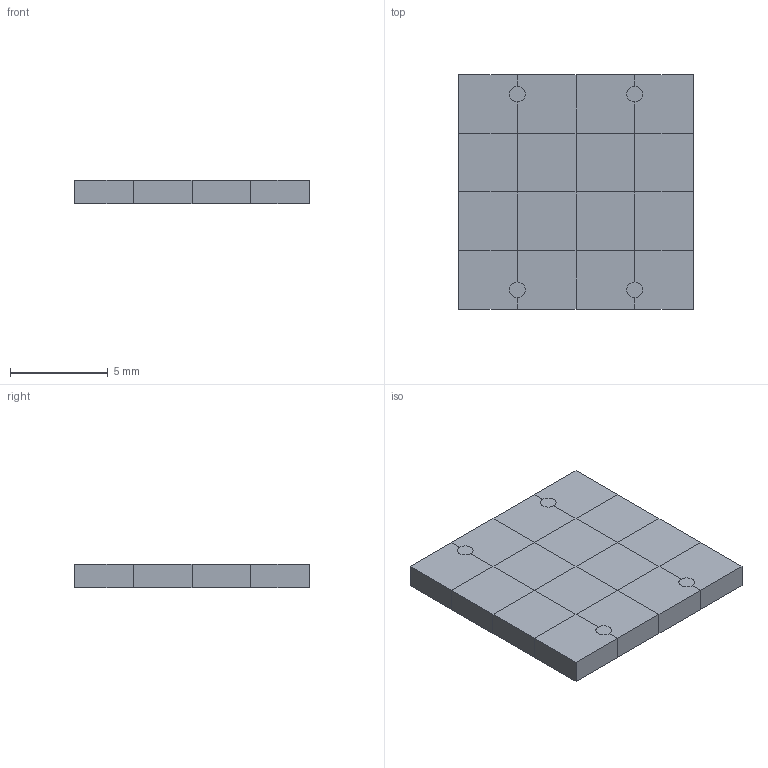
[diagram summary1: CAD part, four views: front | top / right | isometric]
STEP (ISO 10303-21) file: header records copied from the file, then geometry measured from it (millimetres).
FILE_DESCRIPTION(('Open CASCADE Model'),'2;1');
FILE_NAME('Open CASCADE Shape Model','2026-11-27T10:08:08',('Author'),( 'Open CASCADE'),'Open CASCADE STEP processor 7.9','Open CASCADE 7.9' ,'Unknown');
FILE_SCHEMA(('AUTOMOTIVE_DESIGN { 1 0 10303 214 1 1 1 1 }'));
Length unit declared in the file: millimetre
Products named in the file (3): manifold_N14; fluid; solid
Assembly tree (2 placements, depth 2):
  manifold_N14
    fluid
    solid
Bounding box: 12 x 12 x 1.2 mm (x, y, z)
Volume: 172.8 mm3; surface area: 1497 mm2
Topology: 2 solids, 2 shells, 1772 faces, 6308 edges, 3554 vertices
Faces by surface type: plane 1764, cylinder 8
Full cylindrical faces by diameter (mm): 0.8 x8
Entity records: 147670 total; most frequent: CARTESIAN_POINT 24301, DIRECTION 22490, LINE 18876, VECTOR 18876, ORIENTED_EDGE 12616, PCURVE 12616, DEFINITIONAL_REPRESENTATION 12616, EDGE_CURVE 6308
One B-rep face of a CAD part: STEP entity #79262.
In plain terms, the planar face has unit normal (0, 0, 1).
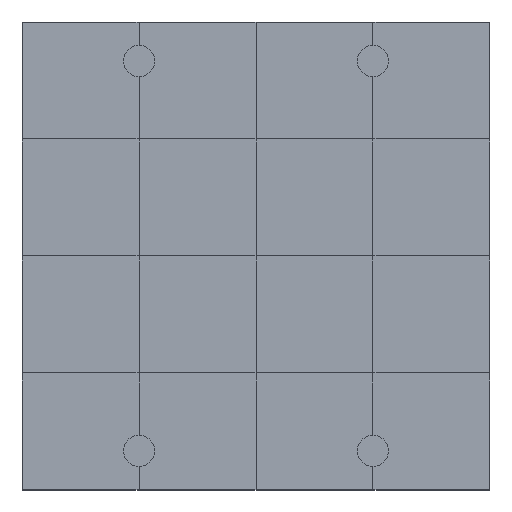
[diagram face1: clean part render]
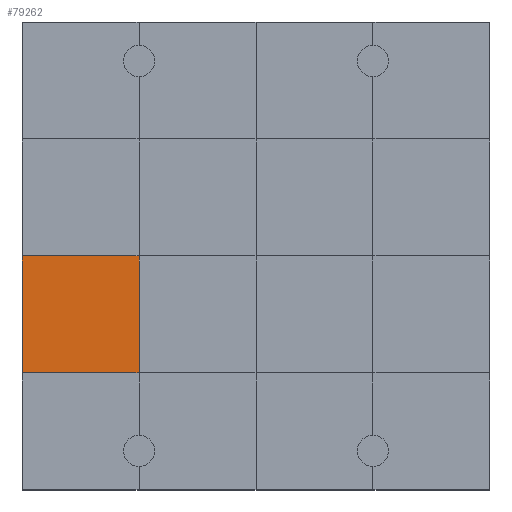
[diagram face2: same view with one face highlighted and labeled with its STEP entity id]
Its self-contained STEP definition (entity closure, numbers rounded to 3 decimals):
#78812 = VERTEX_POINT('',#78813);
#78813 = CARTESIAN_POINT('',(0.,3.,1.2));
#78827 = PLANE('',#78828);
#78828 = AXIS2_PLACEMENT_3D('',#78829,#78830,#78831);
#78829 = CARTESIAN_POINT('',(0.,3.,0.));
#78830 = DIRECTION('',(1.,0.,-0.));
#78831 = DIRECTION('',(0.,0.,1.));
#78853 = PLANE('',#78854);
#78854 = AXIS2_PLACEMENT_3D('',#78855,#78856,#78857);
#78855 = CARTESIAN_POINT('',(0.,0.,1.2));
#78856 = DIRECTION('',(0.,0.,1.));
#78857 = DIRECTION('',(1.,0.,-0.));
#79004 = VERTEX_POINT('',#79005);
#79005 = CARTESIAN_POINT('',(3.,3.,1.2));
#79026 = EDGE_CURVE('',#78812,#79004,#79027,.T.);
#79027 = SURFACE_CURVE('',#79028,(#79032,#79039),.PCURVE_S1.);
#79028 = LINE('',#79029,#79030);
#79029 = CARTESIAN_POINT('',(0.,3.,1.2));
#79030 = VECTOR('',#79031,1.);
#79031 = DIRECTION('',(1.,0.,-0.));
#79032 = PCURVE('',#78853,#79033);
#79033 = DEFINITIONAL_REPRESENTATION('',(#79034),#79038);
#79034 = LINE('',#79035,#79036);
#79035 = CARTESIAN_POINT('',(0.,3.));
#79036 = VECTOR('',#79037,1.);
#79037 = DIRECTION('',(1.,0.));
#79038 = ( GEOMETRIC_REPRESENTATION_CONTEXT(2) 
PARAMETRIC_REPRESENTATION_CONTEXT() REPRESENTATION_CONTEXT('2D SPACE',''
  ) );
#79039 = PCURVE('',#79040,#79045);
#79040 = PLANE('',#79041);
#79041 = AXIS2_PLACEMENT_3D('',#79042,#79043,#79044);
#79042 = CARTESIAN_POINT('',(0.,3.,1.2));
#79043 = DIRECTION('',(0.,0.,1.));
#79044 = DIRECTION('',(1.,0.,-0.));
#79045 = DEFINITIONAL_REPRESENTATION('',(#79046),#79050);
#79046 = LINE('',#79047,#79048);
#79047 = CARTESIAN_POINT('',(0.,0.));
#79048 = VECTOR('',#79049,1.);
#79049 = DIRECTION('',(1.,0.));
#79050 = ( GEOMETRIC_REPRESENTATION_CONTEXT(2) 
PARAMETRIC_REPRESENTATION_CONTEXT() REPRESENTATION_CONTEXT('2D SPACE',''
  ) );
#79085 = VERTEX_POINT('',#79086);
#79086 = CARTESIAN_POINT('',(0.,6.,1.2));
#79112 = EDGE_CURVE('',#78812,#79085,#79113,.T.);
#79113 = SURFACE_CURVE('',#79114,(#79118,#79125),.PCURVE_S1.);
#79114 = LINE('',#79115,#79116);
#79115 = CARTESIAN_POINT('',(0.,3.,1.2));
#79116 = VECTOR('',#79117,1.);
#79117 = DIRECTION('',(-0.,1.,0.));
#79118 = PCURVE('',#78827,#79119);
#79119 = DEFINITIONAL_REPRESENTATION('',(#79120),#79124);
#79120 = LINE('',#79121,#79122);
#79121 = CARTESIAN_POINT('',(1.2,0.));
#79122 = VECTOR('',#79123,1.);
#79123 = DIRECTION('',(0.,-1.));
#79124 = ( GEOMETRIC_REPRESENTATION_CONTEXT(2) 
PARAMETRIC_REPRESENTATION_CONTEXT() REPRESENTATION_CONTEXT('2D SPACE',''
  ) );
#79125 = PCURVE('',#79040,#79126);
#79126 = DEFINITIONAL_REPRESENTATION('',(#79127),#79131);
#79127 = LINE('',#79128,#79129);
#79128 = CARTESIAN_POINT('',(0.,0.));
#79129 = VECTOR('',#79130,1.);
#79130 = DIRECTION('',(0.,1.));
#79131 = ( GEOMETRIC_REPRESENTATION_CONTEXT(2) 
PARAMETRIC_REPRESENTATION_CONTEXT() REPRESENTATION_CONTEXT('2D SPACE',''
  ) );
#79262 = ADVANCED_FACE('',(#79263),#79040,.T.);
#79263 = FACE_BOUND('',#79264,.T.);
#79264 = EDGE_LOOP('',(#79265,#79266,#79267,#79295));
#79265 = ORIENTED_EDGE('',*,*,#79112,.F.);
#79266 = ORIENTED_EDGE('',*,*,#79026,.T.);
#79267 = ORIENTED_EDGE('',*,*,#79268,.T.);
#79268 = EDGE_CURVE('',#79004,#79269,#79271,.T.);
#79269 = VERTEX_POINT('',#79270);
#79270 = CARTESIAN_POINT('',(3.,6.,1.2));
#79271 = SURFACE_CURVE('',#79272,(#79276,#79283),.PCURVE_S1.);
#79272 = LINE('',#79273,#79274);
#79273 = CARTESIAN_POINT('',(3.,3.,1.2));
#79274 = VECTOR('',#79275,1.);
#79275 = DIRECTION('',(-0.,1.,0.));
#79276 = PCURVE('',#79040,#79277);
#79277 = DEFINITIONAL_REPRESENTATION('',(#79278),#79282);
#79278 = LINE('',#79279,#79280);
#79279 = CARTESIAN_POINT('',(3.,0.));
#79280 = VECTOR('',#79281,1.);
#79281 = DIRECTION('',(0.,1.));
#79282 = ( GEOMETRIC_REPRESENTATION_CONTEXT(2) 
PARAMETRIC_REPRESENTATION_CONTEXT() REPRESENTATION_CONTEXT('2D SPACE',''
  ) );
#79283 = PCURVE('',#79284,#79289);
#79284 = PLANE('',#79285);
#79285 = AXIS2_PLACEMENT_3D('',#79286,#79287,#79288);
#79286 = CARTESIAN_POINT('',(3.,3.,1.2));
#79287 = DIRECTION('',(0.,0.,1.));
#79288 = DIRECTION('',(1.,0.,-0.));
#79289 = DEFINITIONAL_REPRESENTATION('',(#79290),#79294);
#79290 = LINE('',#79291,#79292);
#79291 = CARTESIAN_POINT('',(0.,0.));
#79292 = VECTOR('',#79293,1.);
#79293 = DIRECTION('',(0.,1.));
#79294 = ( GEOMETRIC_REPRESENTATION_CONTEXT(2) 
PARAMETRIC_REPRESENTATION_CONTEXT() REPRESENTATION_CONTEXT('2D SPACE',''
  ) );
#79295 = ORIENTED_EDGE('',*,*,#79296,.F.);
#79296 = EDGE_CURVE('',#79085,#79269,#79297,.T.);
#79297 = SURFACE_CURVE('',#79298,(#79302,#79309),.PCURVE_S1.);
#79298 = LINE('',#79299,#79300);
#79299 = CARTESIAN_POINT('',(0.,6.,1.2));
#79300 = VECTOR('',#79301,1.);
#79301 = DIRECTION('',(1.,0.,-0.));
#79302 = PCURVE('',#79040,#79303);
#79303 = DEFINITIONAL_REPRESENTATION('',(#79304),#79308);
#79304 = LINE('',#79305,#79306);
#79305 = CARTESIAN_POINT('',(0.,3.));
#79306 = VECTOR('',#79307,1.);
#79307 = DIRECTION('',(1.,0.));
#79308 = ( GEOMETRIC_REPRESENTATION_CONTEXT(2) 
PARAMETRIC_REPRESENTATION_CONTEXT() REPRESENTATION_CONTEXT('2D SPACE',''
  ) );
#79309 = PCURVE('',#79310,#79315);
#79310 = PLANE('',#79311);
#79311 = AXIS2_PLACEMENT_3D('',#79312,#79313,#79314);
#79312 = CARTESIAN_POINT('',(0.,6.,1.2));
#79313 = DIRECTION('',(0.,0.,1.));
#79314 = DIRECTION('',(1.,0.,-0.));
#79315 = DEFINITIONAL_REPRESENTATION('',(#79316),#79320);
#79316 = LINE('',#79317,#79318);
#79317 = CARTESIAN_POINT('',(0.,0.));
#79318 = VECTOR('',#79319,1.);
#79319 = DIRECTION('',(1.,0.));
#79320 = ( GEOMETRIC_REPRESENTATION_CONTEXT(2) 
PARAMETRIC_REPRESENTATION_CONTEXT() REPRESENTATION_CONTEXT('2D SPACE',''
  ) );
